VERSION 5.7 ;
  NOWIREEXTENSIONATPIN ON ;
  DIVIDERCHAR "/" ;
  BUSBITCHARS "[]" ;
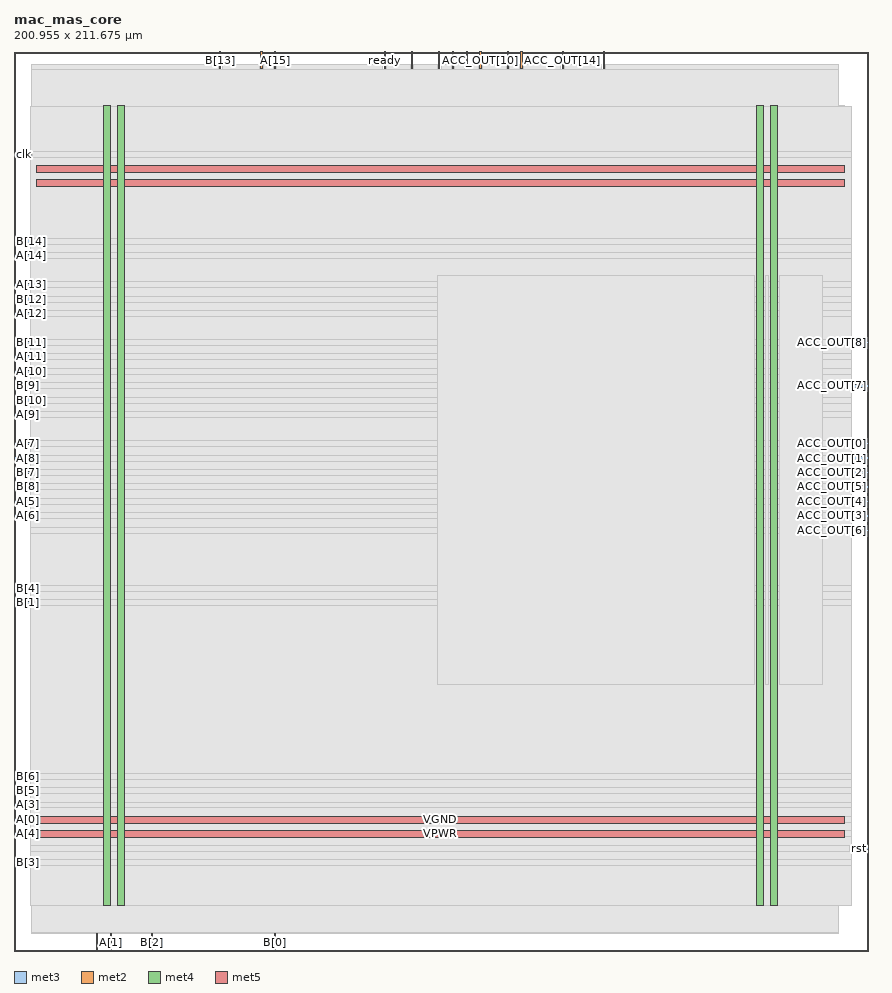
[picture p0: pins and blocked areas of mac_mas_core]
MACRO mac_mas_core
  CLASS BLOCK ;
  FOREIGN mac_mas_core ;
  ORIGIN 0.000 0.000 ;
  SIZE 200.955 BY 211.675 ;
  PIN ACC_OUT[0]
    DIRECTION OUTPUT ;
    USE SIGNAL ;
    ANTENNADIFFAREA 0.340600 ;
    PORT
      LAYER met3 ;
        RECT 196.955 119.040 200.955 119.640 ;
    END
  END ACC_OUT[0]
  PIN ACC_OUT[10]
    DIRECTION OUTPUT ;
    USE SIGNAL ;
    ANTENNADIFFAREA 0.340600 ;
    PORT
      LAYER met2 ;
        RECT 109.570 207.675 109.850 211.675 ;
    END
  END ACC_OUT[10]
  PIN ACC_OUT[11]
    DIRECTION OUTPUT ;
    USE SIGNAL ;
    ANTENNADIFFAREA 0.340600 ;
    PORT
      LAYER met2 ;
        RECT 106.350 207.675 106.630 211.675 ;
    END
  END ACC_OUT[11]
  PIN ACC_OUT[12]
    DIRECTION OUTPUT ;
    USE SIGNAL ;
    ANTENNADIFFAREA 0.340600 ;
    PORT
      LAYER met2 ;
        RECT 116.010 207.675 116.290 211.675 ;
    END
  END ACC_OUT[12]
  PIN ACC_OUT[13]
    DIRECTION OUTPUT ;
    USE SIGNAL ;
    ANTENNADIFFAREA 0.340600 ;
    PORT
      LAYER met2 ;
        RECT 119.230 207.675 119.510 211.675 ;
    END
  END ACC_OUT[13]
  PIN ACC_OUT[14]
    DIRECTION OUTPUT ;
    USE SIGNAL ;
    ANTENNADIFFAREA 0.340600 ;
    PORT
      LAYER met2 ;
        RECT 128.890 207.675 129.170 211.675 ;
    END
  END ACC_OUT[14]
  PIN ACC_OUT[15]
    DIRECTION OUTPUT ;
    USE SIGNAL ;
    ANTENNADIFFAREA 0.340600 ;
    PORT
      LAYER met2 ;
        RECT 138.550 207.675 138.830 211.675 ;
    END
  END ACC_OUT[15]
  PIN ACC_OUT[1]
    DIRECTION OUTPUT ;
    USE SIGNAL ;
    ANTENNADIFFAREA 0.340600 ;
    PORT
      LAYER met3 ;
        RECT 196.955 115.640 200.955 116.240 ;
    END
  END ACC_OUT[1]
  PIN ACC_OUT[2]
    DIRECTION OUTPUT ;
    USE SIGNAL ;
    ANTENNADIFFAREA 0.340600 ;
    PORT
      LAYER met3 ;
        RECT 196.955 112.240 200.955 112.840 ;
    END
  END ACC_OUT[2]
  PIN ACC_OUT[3]
    DIRECTION OUTPUT ;
    USE SIGNAL ;
    ANTENNADIFFAREA 0.340600 ;
    PORT
      LAYER met3 ;
        RECT 196.955 102.040 200.955 102.640 ;
    END
  END ACC_OUT[3]
  PIN ACC_OUT[4]
    DIRECTION OUTPUT ;
    USE SIGNAL ;
    ANTENNADIFFAREA 0.340600 ;
    PORT
      LAYER met3 ;
        RECT 196.955 105.440 200.955 106.040 ;
    END
  END ACC_OUT[4]
  PIN ACC_OUT[5]
    DIRECTION OUTPUT ;
    USE SIGNAL ;
    ANTENNADIFFAREA 0.340600 ;
    PORT
      LAYER met3 ;
        RECT 196.955 108.840 200.955 109.440 ;
    END
  END ACC_OUT[5]
  PIN ACC_OUT[6]
    DIRECTION OUTPUT ;
    USE SIGNAL ;
    ANTENNADIFFAREA 0.340600 ;
    PORT
      LAYER met3 ;
        RECT 196.955 98.640 200.955 99.240 ;
    END
  END ACC_OUT[6]
  PIN ACC_OUT[7]
    DIRECTION OUTPUT ;
    USE SIGNAL ;
    ANTENNADIFFAREA 0.340600 ;
    PORT
      LAYER met3 ;
        RECT 196.955 132.640 200.955 133.240 ;
    END
  END ACC_OUT[7]
  PIN ACC_OUT[8]
    DIRECTION OUTPUT ;
    USE SIGNAL ;
    ANTENNADIFFAREA 0.340600 ;
    PORT
      LAYER met3 ;
        RECT 196.955 142.840 200.955 143.440 ;
    END
  END ACC_OUT[8]
  PIN ACC_OUT[9]
    DIRECTION OUTPUT ;
    USE SIGNAL ;
    ANTENNADIFFAREA 0.340600 ;
    PORT
      LAYER met2 ;
        RECT 103.130 207.675 103.410 211.675 ;
    END
  END ACC_OUT[9]
  PIN A[0]
    DIRECTION INPUT ;
    USE SIGNAL ;
    ANTENNAGATEAREA 0.196500 ;
    PORT
      LAYER met3 ;
        RECT 0.000 30.640 4.000 31.240 ;
    END
  END A[0]
  PIN A[10]
    DIRECTION INPUT ;
    USE SIGNAL ;
    ANTENNAGATEAREA 0.196500 ;
    PORT
      LAYER met3 ;
        RECT 0.000 136.040 4.000 136.640 ;
    END
  END A[10]
  PIN A[11]
    DIRECTION INPUT ;
    USE SIGNAL ;
    ANTENNAGATEAREA 0.196500 ;
    PORT
      LAYER met3 ;
        RECT 0.000 139.440 4.000 140.040 ;
    END
  END A[11]
  PIN A[12]
    DIRECTION INPUT ;
    USE SIGNAL ;
    ANTENNAGATEAREA 0.196500 ;
    PORT
      LAYER met3 ;
        RECT 0.000 149.640 4.000 150.240 ;
    END
  END A[12]
  PIN A[13]
    DIRECTION INPUT ;
    USE SIGNAL ;
    ANTENNAGATEAREA 0.196500 ;
    PORT
      LAYER met3 ;
        RECT 0.000 156.440 4.000 157.040 ;
    END
  END A[13]
  PIN A[14]
    DIRECTION INPUT ;
    USE SIGNAL ;
    ANTENNAGATEAREA 0.196500 ;
    PORT
      LAYER met3 ;
        RECT 0.000 163.240 4.000 163.840 ;
    END
  END A[14]
  PIN A[15]
    DIRECTION INPUT ;
    USE SIGNAL ;
    ANTENNAGATEAREA 0.196500 ;
    PORT
      LAYER met2 ;
        RECT 61.270 207.675 61.550 211.675 ;
    END
  END A[15]
  PIN A[1]
    DIRECTION INPUT ;
    USE SIGNAL ;
    ANTENNAGATEAREA 0.196500 ;
    PORT
      LAYER met2 ;
        RECT 22.630 0.000 22.910 4.000 ;
    END
  END A[1]
  PIN A[2]
    DIRECTION INPUT ;
    USE SIGNAL ;
    ANTENNAGATEAREA 0.196500 ;
    PORT
      LAYER met2 ;
        RECT 19.410 0.000 19.690 4.000 ;
    END
  END A[2]
  PIN A[3]
    DIRECTION INPUT ;
    USE SIGNAL ;
    ANTENNAGATEAREA 0.196500 ;
    PORT
      LAYER met3 ;
        RECT 0.000 34.040 4.000 34.640 ;
    END
  END A[3]
  PIN A[4]
    DIRECTION INPUT ;
    USE SIGNAL ;
    ANTENNAGATEAREA 0.196500 ;
    PORT
      LAYER met3 ;
        RECT 0.000 27.240 4.000 27.840 ;
    END
  END A[4]
  PIN A[5]
    DIRECTION INPUT ;
    USE SIGNAL ;
    ANTENNAGATEAREA 0.196500 ;
    PORT
      LAYER met3 ;
        RECT 0.000 105.440 4.000 106.040 ;
    END
  END A[5]
  PIN A[6]
    DIRECTION INPUT ;
    USE SIGNAL ;
    ANTENNAGATEAREA 0.196500 ;
    PORT
      LAYER met3 ;
        RECT 0.000 102.040 4.000 102.640 ;
    END
  END A[6]
  PIN A[7]
    DIRECTION INPUT ;
    USE SIGNAL ;
    ANTENNAGATEAREA 0.196500 ;
    PORT
      LAYER met3 ;
        RECT 0.000 119.040 4.000 119.640 ;
    END
  END A[7]
  PIN A[8]
    DIRECTION INPUT ;
    USE SIGNAL ;
    ANTENNAGATEAREA 0.196500 ;
    PORT
      LAYER met3 ;
        RECT 0.000 115.640 4.000 116.240 ;
    END
  END A[8]
  PIN A[9]
    DIRECTION INPUT ;
    USE SIGNAL ;
    ANTENNAGATEAREA 0.196500 ;
    PORT
      LAYER met3 ;
        RECT 0.000 125.840 4.000 126.440 ;
    END
  END A[9]
  PIN B[0]
    DIRECTION INPUT ;
    USE SIGNAL ;
    ANTENNAGATEAREA 0.196500 ;
    PORT
      LAYER met2 ;
        RECT 61.270 0.000 61.550 4.000 ;
    END
  END B[0]
  PIN B[10]
    DIRECTION INPUT ;
    USE SIGNAL ;
    ANTENNAGATEAREA 0.196500 ;
    PORT
      LAYER met3 ;
        RECT 0.000 129.240 4.000 129.840 ;
    END
  END B[10]
  PIN B[11]
    DIRECTION INPUT ;
    USE SIGNAL ;
    ANTENNAGATEAREA 0.196500 ;
    PORT
      LAYER met3 ;
        RECT 0.000 142.840 4.000 143.440 ;
    END
  END B[11]
  PIN B[12]
    DIRECTION INPUT ;
    USE SIGNAL ;
    ANTENNAGATEAREA 0.196500 ;
    PORT
      LAYER met3 ;
        RECT 0.000 153.040 4.000 153.640 ;
    END
  END B[12]
  PIN B[13]
    DIRECTION INPUT ;
    USE SIGNAL ;
    ANTENNAGATEAREA 0.196500 ;
    PORT
      LAYER met2 ;
        RECT 48.390 207.675 48.670 211.675 ;
    END
  END B[13]
  PIN B[14]
    DIRECTION INPUT ;
    USE SIGNAL ;
    ANTENNAGATEAREA 0.196500 ;
    PORT
      LAYER met3 ;
        RECT 0.000 166.640 4.000 167.240 ;
    END
  END B[14]
  PIN B[15]
    DIRECTION INPUT ;
    USE SIGNAL ;
    ANTENNAGATEAREA 0.196500 ;
    PORT
      LAYER met2 ;
        RECT 58.050 207.675 58.330 211.675 ;
    END
  END B[15]
  PIN B[1]
    DIRECTION INPUT ;
    USE SIGNAL ;
    ANTENNAGATEAREA 0.196500 ;
    PORT
      LAYER met3 ;
        RECT 0.000 81.640 4.000 82.240 ;
    END
  END B[1]
  PIN B[2]
    DIRECTION INPUT ;
    USE SIGNAL ;
    ANTENNAGATEAREA 0.196500 ;
    PORT
      LAYER met2 ;
        RECT 32.290 0.000 32.570 4.000 ;
    END
  END B[2]
  PIN B[3]
    DIRECTION INPUT ;
    USE SIGNAL ;
    ANTENNAGATEAREA 0.196500 ;
    PORT
      LAYER met3 ;
        RECT 0.000 20.440 4.000 21.040 ;
    END
  END B[3]
  PIN B[4]
    DIRECTION INPUT ;
    USE SIGNAL ;
    ANTENNAGATEAREA 0.196500 ;
    PORT
      LAYER met3 ;
        RECT 0.000 85.040 4.000 85.640 ;
    END
  END B[4]
  PIN B[5]
    DIRECTION INPUT ;
    USE SIGNAL ;
    ANTENNAGATEAREA 0.196500 ;
    PORT
      LAYER met3 ;
        RECT 0.000 37.440 4.000 38.040 ;
    END
  END B[5]
  PIN B[6]
    DIRECTION INPUT ;
    USE SIGNAL ;
    ANTENNAGATEAREA 0.196500 ;
    PORT
      LAYER met3 ;
        RECT 0.000 40.840 4.000 41.440 ;
    END
  END B[6]
  PIN B[7]
    DIRECTION INPUT ;
    USE SIGNAL ;
    ANTENNAGATEAREA 0.196500 ;
    PORT
      LAYER met3 ;
        RECT 0.000 112.240 4.000 112.840 ;
    END
  END B[7]
  PIN B[8]
    DIRECTION INPUT ;
    USE SIGNAL ;
    ANTENNAGATEAREA 0.196500 ;
    PORT
      LAYER met3 ;
        RECT 0.000 108.840 4.000 109.440 ;
    END
  END B[8]
  PIN B[9]
    DIRECTION INPUT ;
    USE SIGNAL ;
    ANTENNAGATEAREA 0.196500 ;
    PORT
      LAYER met3 ;
        RECT 0.000 132.640 4.000 133.240 ;
    END
  END B[9]
  PIN VGND
    DIRECTION INOUT ;
    USE GROUND ;
    PORT
      LAYER met4 ;
        RECT 24.340 10.640 25.940 198.800 ;
    END
    PORT
      LAYER met4 ;
        RECT 177.940 10.640 179.540 198.800 ;
    END
    PORT
      LAYER met5 ;
        RECT 5.280 30.030 195.280 31.630 ;
    END
    PORT
      LAYER met5 ;
        RECT 5.280 183.210 195.280 184.810 ;
    END
  END VGND
  PIN VPWR
    DIRECTION INOUT ;
    USE POWER ;
    PORT
      LAYER met4 ;
        RECT 21.040 10.640 22.640 198.800 ;
    END
    PORT
      LAYER met4 ;
        RECT 174.640 10.640 176.240 198.800 ;
    END
    PORT
      LAYER met5 ;
        RECT 5.280 26.730 195.280 28.330 ;
    END
    PORT
      LAYER met5 ;
        RECT 5.280 179.910 195.280 181.510 ;
    END
  END VPWR
  PIN clk
    DIRECTION INPUT ;
    USE SIGNAL ;
    ANTENNAGATEAREA 36.410999 ;
    PORT
      LAYER met3 ;
        RECT 0.000 187.040 4.000 187.640 ;
    END
  END clk
  PIN mode
    DIRECTION INPUT ;
    USE SIGNAL ;
    ANTENNAGATEAREA 0.196500 ;
    PORT
      LAYER met2 ;
        RECT 99.910 207.675 100.190 211.675 ;
    END
  END mode
  PIN ready
    DIRECTION OUTPUT ;
    USE SIGNAL ;
    ANTENNADIFFAREA 0.340600 ;
    PORT
      LAYER met2 ;
        RECT 87.030 207.675 87.310 211.675 ;
    END
  END ready
  PIN rst
    DIRECTION INPUT ;
    USE SIGNAL ;
    ANTENNAGATEAREA 0.852000 ;
    PORT
      LAYER met3 ;
        RECT 196.955 23.840 200.955 24.440 ;
    END
  END rst
  PIN start
    DIRECTION INPUT ;
    USE SIGNAL ;
    ANTENNAGATEAREA 0.196500 ;
    PORT
      LAYER met2 ;
        RECT 93.470 207.675 93.750 211.675 ;
    END
  END start
  OBS
      LAYER nwell ;
        RECT 5.330 10.795 195.230 198.750 ;
      LAYER li1 ;
        RECT 5.520 10.795 195.040 198.645 ;
      LAYER met1 ;
        RECT 4.210 10.640 195.040 198.800 ;
      LAYER met2 ;
        RECT 4.230 207.395 48.110 208.490 ;
        RECT 48.950 207.395 57.770 208.490 ;
        RECT 58.610 207.395 60.990 208.490 ;
        RECT 61.830 207.395 86.750 208.490 ;
        RECT 87.590 207.395 93.190 208.490 ;
        RECT 94.030 207.395 99.630 208.490 ;
        RECT 100.470 207.395 102.850 208.490 ;
        RECT 103.690 207.395 106.070 208.490 ;
        RECT 106.910 207.395 109.290 208.490 ;
        RECT 110.130 207.395 115.730 208.490 ;
        RECT 116.570 207.395 118.950 208.490 ;
        RECT 119.790 207.395 128.610 208.490 ;
        RECT 129.450 207.395 138.270 208.490 ;
        RECT 139.110 207.395 194.020 208.490 ;
        RECT 4.230 4.280 194.020 207.395 ;
        RECT 4.230 4.000 19.130 4.280 ;
        RECT 19.970 4.000 22.350 4.280 ;
        RECT 23.190 4.000 32.010 4.280 ;
        RECT 32.850 4.000 60.990 4.280 ;
        RECT 61.830 4.000 194.020 4.280 ;
      LAYER met3 ;
        RECT 3.990 188.040 196.955 198.725 ;
        RECT 4.400 186.640 196.955 188.040 ;
        RECT 3.990 167.640 196.955 186.640 ;
        RECT 4.400 166.240 196.955 167.640 ;
        RECT 3.990 164.240 196.955 166.240 ;
        RECT 4.400 162.840 196.955 164.240 ;
        RECT 3.990 157.440 196.955 162.840 ;
        RECT 4.400 156.040 196.955 157.440 ;
        RECT 3.990 154.040 196.955 156.040 ;
        RECT 4.400 152.640 196.955 154.040 ;
        RECT 3.990 150.640 196.955 152.640 ;
        RECT 4.400 149.240 196.955 150.640 ;
        RECT 3.990 143.840 196.955 149.240 ;
        RECT 4.400 142.440 196.555 143.840 ;
        RECT 3.990 140.440 196.955 142.440 ;
        RECT 4.400 139.040 196.955 140.440 ;
        RECT 3.990 137.040 196.955 139.040 ;
        RECT 4.400 135.640 196.955 137.040 ;
        RECT 3.990 133.640 196.955 135.640 ;
        RECT 4.400 132.240 196.555 133.640 ;
        RECT 3.990 130.240 196.955 132.240 ;
        RECT 4.400 128.840 196.955 130.240 ;
        RECT 3.990 126.840 196.955 128.840 ;
        RECT 4.400 125.440 196.955 126.840 ;
        RECT 3.990 120.040 196.955 125.440 ;
        RECT 4.400 118.640 196.555 120.040 ;
        RECT 3.990 116.640 196.955 118.640 ;
        RECT 4.400 115.240 196.555 116.640 ;
        RECT 3.990 113.240 196.955 115.240 ;
        RECT 4.400 111.840 196.555 113.240 ;
        RECT 3.990 109.840 196.955 111.840 ;
        RECT 4.400 108.440 196.555 109.840 ;
        RECT 3.990 106.440 196.955 108.440 ;
        RECT 4.400 105.040 196.555 106.440 ;
        RECT 3.990 103.040 196.955 105.040 ;
        RECT 4.400 101.640 196.555 103.040 ;
        RECT 3.990 99.640 196.955 101.640 ;
        RECT 3.990 98.240 196.555 99.640 ;
        RECT 3.990 86.040 196.955 98.240 ;
        RECT 4.400 84.640 196.955 86.040 ;
        RECT 3.990 82.640 196.955 84.640 ;
        RECT 4.400 81.240 196.955 82.640 ;
        RECT 3.990 41.840 196.955 81.240 ;
        RECT 4.400 40.440 196.955 41.840 ;
        RECT 3.990 38.440 196.955 40.440 ;
        RECT 4.400 37.040 196.955 38.440 ;
        RECT 3.990 35.040 196.955 37.040 ;
        RECT 4.400 33.640 196.955 35.040 ;
        RECT 3.990 31.640 196.955 33.640 ;
        RECT 4.400 30.240 196.955 31.640 ;
        RECT 3.990 28.240 196.955 30.240 ;
        RECT 4.400 26.840 196.955 28.240 ;
        RECT 3.990 24.840 196.955 26.840 ;
        RECT 3.990 23.440 196.555 24.840 ;
        RECT 3.990 21.440 196.955 23.440 ;
        RECT 4.400 20.040 196.955 21.440 ;
        RECT 3.990 10.715 196.955 20.040 ;
      LAYER met4 ;
        RECT 99.655 62.735 174.240 158.945 ;
        RECT 176.640 62.735 177.540 158.945 ;
        RECT 179.940 62.735 190.145 158.945 ;
  END
END mac_mas_core
END LIBRARY

